VERSION 5.7 ;
  NAMESCASESENSITIVE ON ;
  NOWIREEXTENSIONATPIN ON ;
  DIVIDERCHAR "/" ;
  BUSBITCHARS "[]" ;
UNITS
  DATABASE MICRONS 200 ;
END UNITS

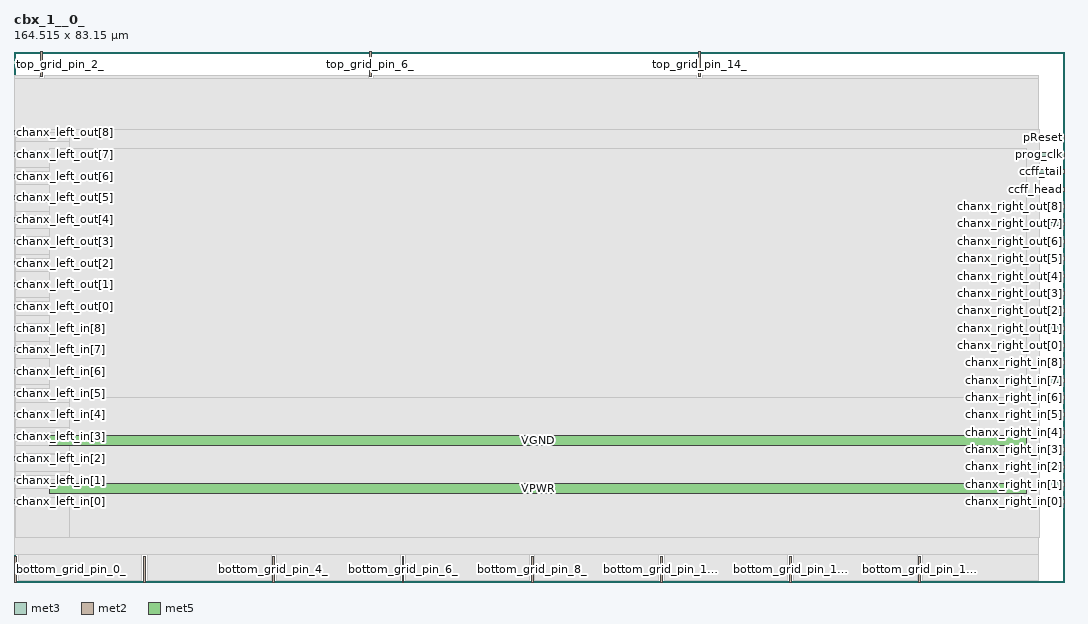
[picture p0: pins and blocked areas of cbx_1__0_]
MACRO cbx_1__0_
  CLASS BLOCK ;
  FOREIGN cbx_1__0_ ;
  ORIGIN 0.000 0.000 ;
  SIZE 164.515 BY 83.150 ;
  PIN chanx_left_in[0]
    DIRECTION INPUT ;
    PORT
      LAYER met3 ;
        RECT 0.000 12.280 4.000 12.880 ;
    END
  END chanx_left_in[0]
  PIN chanx_left_in[1]
    DIRECTION INPUT ;
    PORT
      LAYER met3 ;
        RECT 0.000 15.680 4.000 16.280 ;
    END
  END chanx_left_in[1]
  PIN chanx_left_in[2]
    DIRECTION INPUT ;
    PORT
      LAYER met3 ;
        RECT 0.000 19.080 4.000 19.680 ;
    END
  END chanx_left_in[2]
  PIN chanx_left_in[3]
    DIRECTION INPUT ;
    PORT
      LAYER met3 ;
        RECT 0.000 22.480 4.000 23.080 ;
    END
  END chanx_left_in[3]
  PIN chanx_left_in[4]
    DIRECTION INPUT ;
    PORT
      LAYER met3 ;
        RECT 0.000 25.880 4.000 26.480 ;
    END
  END chanx_left_in[4]
  PIN chanx_left_in[5]
    DIRECTION INPUT ;
    PORT
      LAYER met3 ;
        RECT 0.000 29.280 4.000 29.880 ;
    END
  END chanx_left_in[5]
  PIN chanx_left_in[6]
    DIRECTION INPUT ;
    PORT
      LAYER met3 ;
        RECT 0.000 32.680 4.000 33.280 ;
    END
  END chanx_left_in[6]
  PIN chanx_left_in[7]
    DIRECTION INPUT ;
    PORT
      LAYER met3 ;
        RECT 0.000 36.080 4.000 36.680 ;
    END
  END chanx_left_in[7]
  PIN chanx_left_in[8]
    DIRECTION INPUT ;
    PORT
      LAYER met3 ;
        RECT 0.000 39.480 4.000 40.080 ;
    END
  END chanx_left_in[8]
  PIN chanx_left_out[0]
    DIRECTION OUTPUT TRISTATE ;
    PORT
      LAYER met3 ;
        RECT 0.000 42.880 4.000 43.480 ;
    END
  END chanx_left_out[0]
  PIN chanx_left_out[1]
    DIRECTION OUTPUT TRISTATE ;
    PORT
      LAYER met3 ;
        RECT 0.000 46.280 4.000 46.880 ;
    END
  END chanx_left_out[1]
  PIN chanx_left_out[2]
    DIRECTION OUTPUT TRISTATE ;
    PORT
      LAYER met3 ;
        RECT 0.000 49.680 4.000 50.280 ;
    END
  END chanx_left_out[2]
  PIN chanx_left_out[3]
    DIRECTION OUTPUT TRISTATE ;
    PORT
      LAYER met3 ;
        RECT 0.000 53.080 4.000 53.680 ;
    END
  END chanx_left_out[3]
  PIN chanx_left_out[4]
    DIRECTION OUTPUT TRISTATE ;
    PORT
      LAYER met3 ;
        RECT 0.000 56.480 4.000 57.080 ;
    END
  END chanx_left_out[4]
  PIN chanx_left_out[5]
    DIRECTION OUTPUT TRISTATE ;
    PORT
      LAYER met3 ;
        RECT 0.000 59.880 4.000 60.480 ;
    END
  END chanx_left_out[5]
  PIN chanx_left_out[6]
    DIRECTION OUTPUT TRISTATE ;
    PORT
      LAYER met3 ;
        RECT 0.000 63.280 4.000 63.880 ;
    END
  END chanx_left_out[6]
  PIN chanx_left_out[7]
    DIRECTION OUTPUT TRISTATE ;
    PORT
      LAYER met3 ;
        RECT 0.000 66.680 4.000 67.280 ;
    END
  END chanx_left_out[7]
  PIN chanx_left_out[8]
    DIRECTION OUTPUT TRISTATE ;
    PORT
      LAYER met3 ;
        RECT 0.000 70.080 4.000 70.680 ;
    END
  END chanx_left_out[8]
  PIN top_grid_pin_2_
    DIRECTION OUTPUT TRISTATE ;
    PORT
      LAYER met2 ;
        RECT 4.230 79.150 4.510 83.150 ;
    END
  END top_grid_pin_2_
  PIN top_grid_pin_6_
    DIRECTION OUTPUT TRISTATE ;
    PORT
      LAYER met2 ;
        RECT 55.750 79.150 56.030 83.150 ;
    END
  END top_grid_pin_6_
  PIN top_grid_pin_14_
    DIRECTION OUTPUT TRISTATE ;
    PORT
      LAYER met2 ;
        RECT 107.270 79.150 107.550 83.150 ;
    END
  END top_grid_pin_14_
  PIN chanx_right_in[0]
    DIRECTION INPUT ;
    PORT
      LAYER met3 ;
        RECT 160.515 12.280 164.515 12.880 ;
    END
  END chanx_right_in[0]
  PIN chanx_right_in[1]
    DIRECTION INPUT ;
    PORT
      LAYER met3 ;
        RECT 160.515 15.000 164.515 15.600 ;
    END
  END chanx_right_in[1]
  PIN chanx_right_in[2]
    DIRECTION INPUT ;
    PORT
      LAYER met3 ;
        RECT 160.515 17.720 164.515 18.320 ;
    END
  END chanx_right_in[2]
  PIN chanx_right_in[3]
    DIRECTION INPUT ;
    PORT
      LAYER met3 ;
        RECT 160.515 20.440 164.515 21.040 ;
    END
  END chanx_right_in[3]
  PIN chanx_right_in[4]
    DIRECTION INPUT ;
    PORT
      LAYER met3 ;
        RECT 160.515 23.160 164.515 23.760 ;
    END
  END chanx_right_in[4]
  PIN chanx_right_in[5]
    DIRECTION INPUT ;
    PORT
      LAYER met3 ;
        RECT 160.515 25.880 164.515 26.480 ;
    END
  END chanx_right_in[5]
  PIN chanx_right_in[6]
    DIRECTION INPUT ;
    PORT
      LAYER met3 ;
        RECT 160.515 28.600 164.515 29.200 ;
    END
  END chanx_right_in[6]
  PIN chanx_right_in[7]
    DIRECTION INPUT ;
    PORT
      LAYER met3 ;
        RECT 160.515 31.320 164.515 31.920 ;
    END
  END chanx_right_in[7]
  PIN chanx_right_in[8]
    DIRECTION INPUT ;
    PORT
      LAYER met3 ;
        RECT 160.515 34.040 164.515 34.640 ;
    END
  END chanx_right_in[8]
  PIN chanx_right_out[0]
    DIRECTION OUTPUT TRISTATE ;
    PORT
      LAYER met3 ;
        RECT 160.515 36.760 164.515 37.360 ;
    END
  END chanx_right_out[0]
  PIN chanx_right_out[1]
    DIRECTION OUTPUT TRISTATE ;
    PORT
      LAYER met3 ;
        RECT 160.515 39.480 164.515 40.080 ;
    END
  END chanx_right_out[1]
  PIN chanx_right_out[2]
    DIRECTION OUTPUT TRISTATE ;
    PORT
      LAYER met3 ;
        RECT 160.515 42.200 164.515 42.800 ;
    END
  END chanx_right_out[2]
  PIN chanx_right_out[3]
    DIRECTION OUTPUT TRISTATE ;
    PORT
      LAYER met3 ;
        RECT 160.515 44.920 164.515 45.520 ;
    END
  END chanx_right_out[3]
  PIN chanx_right_out[4]
    DIRECTION OUTPUT TRISTATE ;
    PORT
      LAYER met3 ;
        RECT 160.515 47.640 164.515 48.240 ;
    END
  END chanx_right_out[4]
  PIN chanx_right_out[5]
    DIRECTION OUTPUT TRISTATE ;
    PORT
      LAYER met3 ;
        RECT 160.515 50.360 164.515 50.960 ;
    END
  END chanx_right_out[5]
  PIN chanx_right_out[6]
    DIRECTION OUTPUT TRISTATE ;
    PORT
      LAYER met3 ;
        RECT 160.515 53.080 164.515 53.680 ;
    END
  END chanx_right_out[6]
  PIN chanx_right_out[7]
    DIRECTION OUTPUT TRISTATE ;
    PORT
      LAYER met3 ;
        RECT 160.515 55.800 164.515 56.400 ;
    END
  END chanx_right_out[7]
  PIN chanx_right_out[8]
    DIRECTION OUTPUT TRISTATE ;
    PORT
      LAYER met3 ;
        RECT 160.515 58.520 164.515 59.120 ;
    END
  END chanx_right_out[8]
  PIN ccff_head
    DIRECTION INPUT ;
    PORT
      LAYER met3 ;
        RECT 160.515 61.240 164.515 61.840 ;
    END
  END ccff_head
  PIN ccff_tail
    DIRECTION OUTPUT TRISTATE ;
    PORT
      LAYER met3 ;
        RECT 160.515 63.960 164.515 64.560 ;
    END
  END ccff_tail
  PIN prog_clk
    DIRECTION INPUT ;
    PORT
      LAYER met3 ;
        RECT 160.515 66.680 164.515 67.280 ;
    END
  END prog_clk
  PIN pReset
    DIRECTION INPUT ;
    PORT
      LAYER met3 ;
        RECT 160.515 69.400 164.515 70.000 ;
    END
  END pReset
  PIN bottom_grid_pin_0_
    DIRECTION OUTPUT TRISTATE ;
    PORT
      LAYER met2 ;
        RECT 0.090 0.000 0.370 4.000 ;
    END
  END bottom_grid_pin_0_
  PIN bottom_grid_pin_2_
    DIRECTION OUTPUT TRISTATE ;
    PORT
      LAYER met2 ;
        RECT 20.330 0.000 20.610 4.000 ;
    END
  END bottom_grid_pin_2_
  PIN bottom_grid_pin_4_
    DIRECTION OUTPUT TRISTATE ;
    PORT
      LAYER met2 ;
        RECT 40.570 0.000 40.850 4.000 ;
    END
  END bottom_grid_pin_4_
  PIN bottom_grid_pin_6_
    DIRECTION OUTPUT TRISTATE ;
    PORT
      LAYER met2 ;
        RECT 60.810 0.000 61.090 4.000 ;
    END
  END bottom_grid_pin_6_
  PIN bottom_grid_pin_8_
    DIRECTION OUTPUT TRISTATE ;
    PORT
      LAYER met2 ;
        RECT 81.050 0.000 81.330 4.000 ;
    END
  END bottom_grid_pin_8_
  PIN bottom_grid_pin_10_
    DIRECTION OUTPUT TRISTATE ;
    PORT
      LAYER met2 ;
        RECT 101.290 0.000 101.570 4.000 ;
    END
  END bottom_grid_pin_10_
  PIN bottom_grid_pin_12_
    DIRECTION OUTPUT TRISTATE ;
    PORT
      LAYER met2 ;
        RECT 121.530 0.000 121.810 4.000 ;
    END
  END bottom_grid_pin_12_
  PIN bottom_grid_pin_14_
    DIRECTION OUTPUT TRISTATE ;
    PORT
      LAYER met2 ;
        RECT 141.770 0.000 142.050 4.000 ;
    END
  END bottom_grid_pin_14_
  PIN VPWR
    DIRECTION INPUT ;
    USE POWER ;
    PORT
      LAYER met5 ;
        RECT 5.520 13.840 158.700 15.440 ;
    END
  END VPWR
  PIN VGND
    DIRECTION INPUT ;
    USE GROUND ;
    PORT
      LAYER met5 ;
        RECT 5.520 21.340 158.700 22.940 ;
    END
  END VGND
  OBS
      LAYER li1 ;
        RECT 5.520 10.795 158.700 70.805 ;
      LAYER met1 ;
        RECT 0.070 10.640 158.700 70.960 ;
      LAYER met2 ;
        RECT 0.090 78.870 3.950 79.290 ;
        RECT 4.790 78.870 55.470 79.290 ;
        RECT 56.310 78.870 106.990 79.290 ;
        RECT 107.830 78.870 160.450 79.290 ;
        RECT 0.090 4.280 160.450 78.870 ;
        RECT 0.650 0.270 20.050 4.280 ;
        RECT 20.890 0.270 40.290 4.280 ;
        RECT 41.130 0.270 60.530 4.280 ;
        RECT 61.370 0.270 80.770 4.280 ;
        RECT 81.610 0.270 101.010 4.280 ;
        RECT 101.850 0.270 121.250 4.280 ;
        RECT 122.090 0.270 141.490 4.280 ;
        RECT 142.330 0.270 160.450 4.280 ;
      LAYER met3 ;
        RECT 4.400 70.400 160.730 70.885 ;
        RECT 4.400 69.680 160.115 70.400 ;
        RECT 0.310 69.000 160.115 69.680 ;
        RECT 0.310 67.680 160.730 69.000 ;
        RECT 4.400 66.280 160.115 67.680 ;
        RECT 0.310 64.960 160.730 66.280 ;
        RECT 0.310 64.280 160.115 64.960 ;
        RECT 4.400 63.560 160.115 64.280 ;
        RECT 4.400 62.880 160.730 63.560 ;
        RECT 0.310 62.240 160.730 62.880 ;
        RECT 0.310 60.880 160.115 62.240 ;
        RECT 4.400 60.840 160.115 60.880 ;
        RECT 4.400 59.520 160.730 60.840 ;
        RECT 4.400 59.480 160.115 59.520 ;
        RECT 0.310 58.120 160.115 59.480 ;
        RECT 0.310 57.480 160.730 58.120 ;
        RECT 4.400 56.800 160.730 57.480 ;
        RECT 4.400 56.080 160.115 56.800 ;
        RECT 0.310 55.400 160.115 56.080 ;
        RECT 0.310 54.080 160.730 55.400 ;
        RECT 4.400 52.680 160.115 54.080 ;
        RECT 0.310 51.360 160.730 52.680 ;
        RECT 0.310 50.680 160.115 51.360 ;
        RECT 4.400 49.960 160.115 50.680 ;
        RECT 4.400 49.280 160.730 49.960 ;
        RECT 0.310 48.640 160.730 49.280 ;
        RECT 0.310 47.280 160.115 48.640 ;
        RECT 4.400 47.240 160.115 47.280 ;
        RECT 4.400 45.920 160.730 47.240 ;
        RECT 4.400 45.880 160.115 45.920 ;
        RECT 0.310 44.520 160.115 45.880 ;
        RECT 0.310 43.880 160.730 44.520 ;
        RECT 4.400 43.200 160.730 43.880 ;
        RECT 4.400 42.480 160.115 43.200 ;
        RECT 0.310 41.800 160.115 42.480 ;
        RECT 0.310 40.480 160.730 41.800 ;
        RECT 4.400 39.080 160.115 40.480 ;
        RECT 0.310 37.760 160.730 39.080 ;
        RECT 0.310 37.080 160.115 37.760 ;
        RECT 4.400 36.360 160.115 37.080 ;
        RECT 4.400 35.680 160.730 36.360 ;
        RECT 0.310 35.040 160.730 35.680 ;
        RECT 0.310 33.680 160.115 35.040 ;
        RECT 4.400 33.640 160.115 33.680 ;
        RECT 4.400 32.320 160.730 33.640 ;
        RECT 4.400 32.280 160.115 32.320 ;
        RECT 0.310 30.920 160.115 32.280 ;
        RECT 0.310 30.280 160.730 30.920 ;
        RECT 4.400 29.600 160.730 30.280 ;
        RECT 4.400 28.880 160.115 29.600 ;
        RECT 0.310 28.200 160.115 28.880 ;
        RECT 0.310 26.880 160.730 28.200 ;
        RECT 4.400 25.480 160.115 26.880 ;
        RECT 0.310 24.160 160.730 25.480 ;
        RECT 0.310 23.480 160.115 24.160 ;
        RECT 4.400 22.760 160.115 23.480 ;
        RECT 4.400 22.080 160.730 22.760 ;
        RECT 0.310 21.440 160.730 22.080 ;
        RECT 0.310 20.080 160.115 21.440 ;
        RECT 4.400 20.040 160.115 20.080 ;
        RECT 4.400 18.720 160.730 20.040 ;
        RECT 4.400 18.680 160.115 18.720 ;
        RECT 0.310 17.320 160.115 18.680 ;
        RECT 0.310 16.680 160.730 17.320 ;
        RECT 4.400 16.000 160.730 16.680 ;
        RECT 4.400 15.280 160.115 16.000 ;
        RECT 0.310 14.600 160.115 15.280 ;
        RECT 0.310 13.280 160.730 14.600 ;
        RECT 4.400 11.880 160.115 13.280 ;
        RECT 0.310 6.975 160.730 11.880 ;
      LAYER met4 ;
        RECT 8.720 6.975 160.705 70.960 ;
      LAYER met5 ;
        RECT 5.520 28.840 158.700 67.940 ;
  END
END cbx_1__0_
END LIBRARY

